VERSION 5.7 ;
  NOWIREEXTENSIONATPIN ON ;
  DIVIDERCHAR "/" ;
  BUSBITCHARS "[]" ;
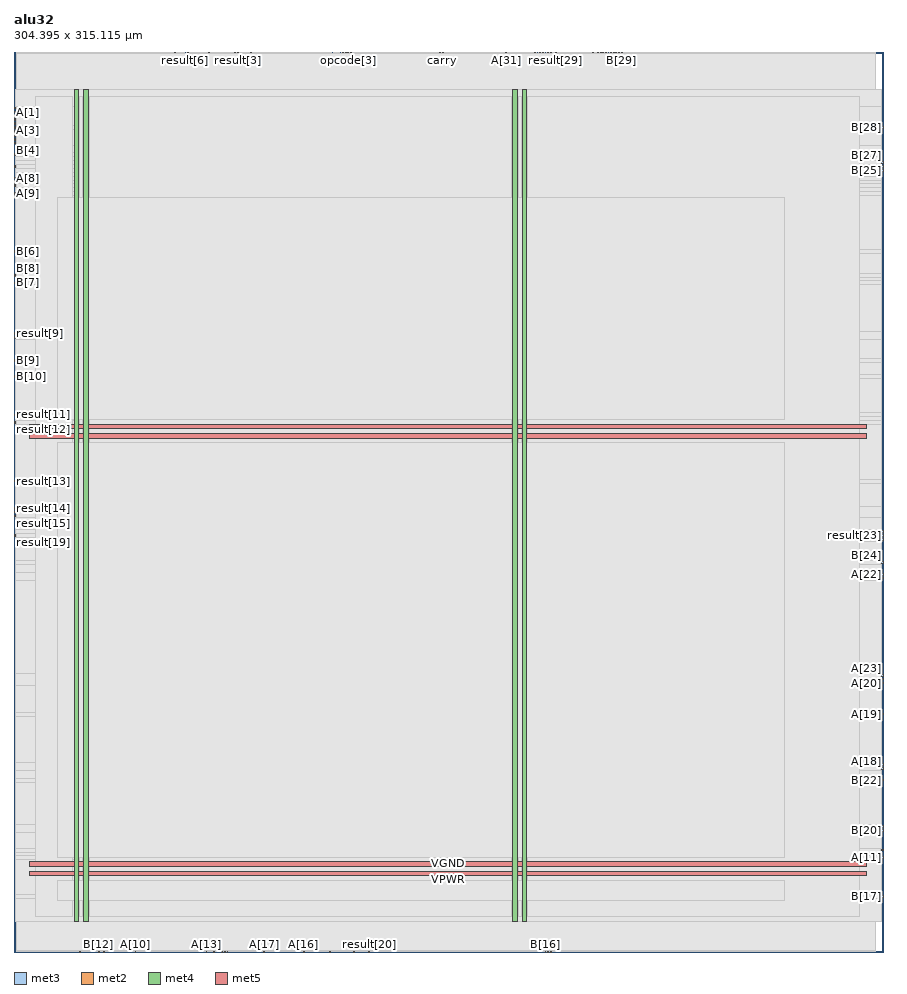
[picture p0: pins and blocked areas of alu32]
MACRO alu32
  CLASS BLOCK ;
  FOREIGN alu32 ;
  ORIGIN 0.000 0.000 ;
  SIZE 304.395 BY 315.115 ;
  PIN A[0]
    DIRECTION INPUT ;
    USE SIGNAL ;
    ANTENNAGATEAREA 0.126000 ;
    PORT
      LAYER met3 ;
        RECT 0.000 292.440 0.600 293.040 ;
    END
  END A[0]
  PIN A[10]
    DIRECTION INPUT ;
    USE SIGNAL ;
    ANTENNAGATEAREA 0.213000 ;
    PORT
      LAYER met2 ;
        RECT 42.410 0.000 42.690 0.280 ;
    END
  END A[10]
  PIN A[11]
    DIRECTION INPUT ;
    USE SIGNAL ;
    ANTENNAGATEAREA 0.213000 ;
    PORT
      LAYER met3 ;
        RECT 303.795 32.680 304.395 33.280 ;
    END
  END A[11]
  PIN A[12]
    DIRECTION INPUT ;
    USE SIGNAL ;
    ANTENNAGATEAREA 0.247500 ;
    PORT
      LAYER met3 ;
        RECT 303.795 35.400 304.395 36.000 ;
    END
  END A[12]
  PIN A[13]
    DIRECTION INPUT ;
    USE SIGNAL ;
    ANTENNAGATEAREA 0.196500 ;
    PORT
      LAYER met2 ;
        RECT 67.250 0.000 67.530 0.280 ;
    END
  END A[13]
  PIN A[14]
    DIRECTION INPUT ;
    USE SIGNAL ;
    ANTENNAGATEAREA 0.213000 ;
    PORT
      LAYER met2 ;
        RECT 70.010 0.000 70.290 0.280 ;
    END
  END A[14]
  PIN A[15]
    DIRECTION INPUT ;
    USE SIGNAL ;
    ANTENNAGATEAREA 0.213000 ;
    PORT
      LAYER met2 ;
        RECT 73.690 0.000 73.970 0.280 ;
    END
  END A[15]
  PIN A[16]
    DIRECTION INPUT ;
    USE SIGNAL ;
    ANTENNAGATEAREA 0.213000 ;
    PORT
      LAYER met2 ;
        RECT 101.290 0.000 101.570 0.280 ;
    END
  END A[16]
  PIN A[17]
    DIRECTION INPUT ;
    USE SIGNAL ;
    ANTENNAGATEAREA 0.196500 ;
    PORT
      LAYER met2 ;
        RECT 87.490 0.000 87.770 0.280 ;
    END
  END A[17]
  PIN A[18]
    DIRECTION INPUT ;
    USE SIGNAL ;
    ANTENNAGATEAREA 0.213000 ;
    PORT
      LAYER met3 ;
        RECT 303.795 63.960 304.395 64.560 ;
    END
  END A[18]
  PIN A[19]
    DIRECTION INPUT ;
    USE SIGNAL ;
    ANTENNAGATEAREA 0.213000 ;
    PORT
      LAYER met3 ;
        RECT 303.795 83.000 304.395 83.600 ;
    END
  END A[19]
  PIN A[1]
    DIRECTION INPUT ;
    USE SIGNAL ;
    ANTENNAGATEAREA 0.495000 ;
    PORT
      LAYER met3 ;
        RECT 0.000 293.800 0.600 294.400 ;
    END
  END A[1]
  PIN A[20]
    DIRECTION INPUT ;
    USE SIGNAL ;
    ANTENNAGATEAREA 0.213000 ;
    PORT
      LAYER met3 ;
        RECT 303.795 93.880 304.395 94.480 ;
    END
  END A[20]
  PIN A[21]
    DIRECTION INPUT ;
    USE SIGNAL ;
    ANTENNAGATEAREA 0.126000 ;
    PORT
      LAYER met3 ;
        RECT 303.795 95.240 304.395 95.840 ;
    END
  END A[21]
  PIN A[22]
    DIRECTION INPUT ;
    USE SIGNAL ;
    ANTENNAGATEAREA 0.126000 ;
    PORT
      LAYER met3 ;
        RECT 303.795 131.960 304.395 132.560 ;
    END
  END A[22]
  PIN A[23]
    DIRECTION INPUT ;
    USE SIGNAL ;
    ANTENNAGATEAREA 0.213000 ;
    PORT
      LAYER met3 ;
        RECT 303.795 96.600 304.395 97.200 ;
    END
  END A[23]
  PIN A[24]
    DIRECTION INPUT ;
    USE SIGNAL ;
    ANTENNAGATEAREA 0.213000 ;
    PORT
      LAYER met2 ;
        RECT 208.010 314.835 208.290 315.115 ;
    END
  END A[24]
  PIN A[25]
    DIRECTION INPUT ;
    USE SIGNAL ;
    ANTENNAGATEAREA 0.213000 ;
    PORT
      LAYER met2 ;
        RECT 207.090 314.835 207.370 315.115 ;
    END
  END A[25]
  PIN A[26]
    DIRECTION INPUT ;
    USE SIGNAL ;
    ANTENNAGATEAREA 0.213000 ;
    PORT
      LAYER met2 ;
        RECT 210.770 314.835 211.050 315.115 ;
    END
  END A[26]
  PIN A[27]
    DIRECTION INPUT ;
    USE SIGNAL ;
    ANTENNAGATEAREA 0.213000 ;
    PORT
      LAYER met2 ;
        RECT 211.690 314.835 211.970 315.115 ;
    END
  END A[27]
  PIN A[28]
    DIRECTION INPUT ;
    USE SIGNAL ;
    ANTENNAGATEAREA 0.213000 ;
    PORT
      LAYER met2 ;
        RECT 209.850 314.835 210.130 315.115 ;
    END
  END A[28]
  PIN A[29]
    DIRECTION INPUT ;
    USE SIGNAL ;
    ANTENNAGATEAREA 0.213000 ;
    PORT
      LAYER met2 ;
        RECT 208.930 314.835 209.210 315.115 ;
    END
  END A[29]
  PIN A[2]
    DIRECTION INPUT ;
    USE SIGNAL ;
    ANTENNAGATEAREA 0.213000 ;
    PORT
      LAYER met3 ;
        RECT 0.000 291.080 0.600 291.680 ;
    END
  END A[2]
  PIN A[30]
    DIRECTION INPUT ;
    USE SIGNAL ;
    ANTENNAGATEAREA 0.196500 ;
    PORT
      LAYER met2 ;
        RECT 206.170 314.835 206.450 315.115 ;
    END
  END A[30]
  PIN A[31]
    DIRECTION INPUT ;
    USE SIGNAL ;
    ANTENNAGATEAREA 0.213000 ;
    PORT
      LAYER met2 ;
        RECT 172.130 314.835 172.410 315.115 ;
    END
  END A[31]
  PIN A[3]
    DIRECTION INPUT ;
    USE SIGNAL ;
    ANTENNAGATEAREA 0.247500 ;
    PORT
      LAYER met3 ;
        RECT 0.000 289.720 0.600 290.320 ;
    END
  END A[3]
  PIN A[4]
    DIRECTION INPUT ;
    USE SIGNAL ;
    ANTENNAGATEAREA 0.213000 ;
    PORT
      LAYER met3 ;
        RECT 0.000 288.360 0.600 288.960 ;
    END
  END A[4]
  PIN A[5]
    DIRECTION INPUT ;
    USE SIGNAL ;
    ANTENNAGATEAREA 0.213000 ;
    PORT
      LAYER met3 ;
        RECT 0.000 287.000 0.600 287.600 ;
    END
  END A[5]
  PIN A[6]
    DIRECTION INPUT ;
    USE SIGNAL ;
    ANTENNAGATEAREA 0.213000 ;
    PORT
      LAYER met3 ;
        RECT 0.000 278.840 0.600 279.440 ;
    END
  END A[6]
  PIN A[7]
    DIRECTION INPUT ;
    USE SIGNAL ;
    ANTENNAGATEAREA 0.247500 ;
    PORT
      LAYER met3 ;
        RECT 0.000 274.760 0.600 275.360 ;
    END
  END A[7]
  PIN A[8]
    DIRECTION INPUT ;
    USE SIGNAL ;
    ANTENNAGATEAREA 0.159000 ;
    PORT
      LAYER met3 ;
        RECT 0.000 270.680 0.600 271.280 ;
    END
  END A[8]
  PIN A[9]
    DIRECTION INPUT ;
    USE SIGNAL ;
    ANTENNAGATEAREA 0.213000 ;
    PORT
      LAYER met3 ;
        RECT 0.000 265.240 0.600 265.840 ;
    END
  END A[9]
  PIN B[0]
    DIRECTION INPUT ;
    USE SIGNAL ;
    ANTENNAGATEAREA 0.213000 ;
    PORT
      LAYER met2 ;
        RECT 205.250 314.835 205.530 315.115 ;
    END
  END B[0]
  PIN B[10]
    DIRECTION INPUT ;
    USE SIGNAL ;
    ANTENNAGATEAREA 0.126000 ;
    PORT
      LAYER met3 ;
        RECT 0.000 201.320 0.600 201.920 ;
    END
  END B[10]
  PIN B[11]
    DIRECTION INPUT ;
    USE SIGNAL ;
    ANTENNAGATEAREA 0.213000 ;
    PORT
      LAYER met2 ;
        RECT 23.090 0.000 23.370 0.280 ;
    END
  END B[11]
  PIN B[12]
    DIRECTION INPUT ;
    USE SIGNAL ;
    ANTENNAGATEAREA 0.213000 ;
    PORT
      LAYER met2 ;
        RECT 29.530 0.000 29.810 0.280 ;
    END
  END B[12]
  PIN B[13]
    DIRECTION INPUT ;
    USE SIGNAL ;
    ANTENNAGATEAREA 0.213000 ;
    PORT
      LAYER met2 ;
        RECT 31.370 0.000 31.650 0.280 ;
    END
  END B[13]
  PIN B[14]
    DIRECTION INPUT ;
    USE SIGNAL ;
    ANTENNAGATEAREA 0.126000 ;
    PORT
      LAYER met2 ;
        RECT 72.770 0.000 73.050 0.280 ;
    END
  END B[14]
  PIN B[15]
    DIRECTION INPUT ;
    USE SIGNAL ;
    ANTENNAGATEAREA 0.126000 ;
    PORT
      LAYER met2 ;
        RECT 74.610 0.000 74.890 0.280 ;
    END
  END B[15]
  PIN B[16]
    DIRECTION INPUT ;
    USE SIGNAL ;
    ANTENNAGATEAREA 0.159000 ;
    PORT
      LAYER met2 ;
        RECT 185.930 0.000 186.210 0.280 ;
    END
  END B[16]
  PIN B[17]
    DIRECTION INPUT ;
    USE SIGNAL ;
    ANTENNAGATEAREA 0.213000 ;
    PORT
      LAYER met3 ;
        RECT 303.795 19.080 304.395 19.680 ;
    END
  END B[17]
  PIN B[18]
    DIRECTION INPUT ;
    USE SIGNAL ;
    ANTENNAGATEAREA 0.213000 ;
    PORT
      LAYER met2 ;
        RECT 186.850 0.000 187.130 0.280 ;
    END
  END B[18]
  PIN B[19]
    DIRECTION INPUT ;
    USE SIGNAL ;
    ANTENNAGATEAREA 0.213000 ;
    PORT
      LAYER met2 ;
        RECT 187.770 0.000 188.050 0.280 ;
    END
  END B[19]
  PIN B[1]
    DIRECTION INPUT ;
    USE SIGNAL ;
    ANTENNAGATEAREA 0.213000 ;
    PORT
      LAYER met3 ;
        RECT 0.000 295.160 0.600 295.760 ;
    END
  END B[1]
  PIN B[20]
    DIRECTION INPUT ;
    USE SIGNAL ;
    ANTENNAGATEAREA 0.213000 ;
    PORT
      LAYER met3 ;
        RECT 303.795 42.200 304.395 42.800 ;
    END
  END B[20]
  PIN B[21]
    DIRECTION INPUT ;
    USE SIGNAL ;
    ANTENNAGATEAREA 0.213000 ;
    PORT
      LAYER met3 ;
        RECT 303.795 43.560 304.395 44.160 ;
    END
  END B[21]
  PIN B[22]
    DIRECTION INPUT ;
    USE SIGNAL ;
    ANTENNAGATEAREA 0.213000 ;
    PORT
      LAYER met3 ;
        RECT 303.795 59.880 304.395 60.480 ;
    END
  END B[22]
  PIN B[23]
    DIRECTION INPUT ;
    USE SIGNAL ;
    ANTENNAGATEAREA 0.213000 ;
    PORT
      LAYER met3 ;
        RECT 303.795 65.320 304.395 65.920 ;
    END
  END B[23]
  PIN B[24]
    DIRECTION INPUT ;
    USE SIGNAL ;
    ANTENNAGATEAREA 0.213000 ;
    PORT
      LAYER met3 ;
        RECT 303.795 136.040 304.395 136.640 ;
    END
  END B[24]
  PIN B[25]
    DIRECTION INPUT ;
    USE SIGNAL ;
    ANTENNAGATEAREA 0.213000 ;
    PORT
      LAYER met3 ;
        RECT 303.795 273.400 304.395 274.000 ;
    END
  END B[25]
  PIN B[26]
    DIRECTION INPUT ;
    USE SIGNAL ;
    ANTENNAGATEAREA 0.213000 ;
    PORT
      LAYER met3 ;
        RECT 303.795 274.760 304.395 275.360 ;
    END
  END B[26]
  PIN B[27]
    DIRECTION INPUT ;
    USE SIGNAL ;
    ANTENNAGATEAREA 0.213000 ;
    PORT
      LAYER met3 ;
        RECT 303.795 276.120 304.395 276.720 ;
    END
  END B[27]
  PIN B[28]
    DIRECTION INPUT ;
    USE SIGNAL ;
    ANTENNAGATEAREA 0.196500 ;
    PORT
      LAYER met3 ;
        RECT 303.795 288.360 304.395 288.960 ;
    END
  END B[28]
  PIN B[29]
    DIRECTION INPUT ;
    USE SIGNAL ;
    ANTENNAGATEAREA 0.213000 ;
    PORT
      LAYER met2 ;
        RECT 212.610 314.835 212.890 315.115 ;
    END
  END B[29]
  PIN B[2]
    DIRECTION INPUT ;
    USE SIGNAL ;
    ANTENNAGATEAREA 0.213000 ;
    PORT
      LAYER met3 ;
        RECT 0.000 285.640 0.600 286.240 ;
    END
  END B[2]
  PIN B[30]
    DIRECTION INPUT ;
    USE SIGNAL ;
    ANTENNAGATEAREA 0.213000 ;
    PORT
      LAYER met2 ;
        RECT 204.330 314.835 204.610 315.115 ;
    END
  END B[30]
  PIN B[31]
    DIRECTION INPUT ;
    USE SIGNAL ;
    ANTENNAGATEAREA 0.213000 ;
    PORT
      LAYER met2 ;
        RECT 202.490 314.835 202.770 315.115 ;
    END
  END B[31]
  PIN B[3]
    DIRECTION INPUT ;
    USE SIGNAL ;
    ANTENNAGATEAREA 0.213000 ;
    PORT
      LAYER met3 ;
        RECT 0.000 284.280 0.600 284.880 ;
    END
  END B[3]
  PIN B[4]
    DIRECTION INPUT ;
    USE SIGNAL ;
    ANTENNAGATEAREA 0.213000 ;
    PORT
      LAYER met3 ;
        RECT 0.000 282.920 0.600 283.520 ;
    END
  END B[4]
  PIN B[5]
    DIRECTION INPUT ;
    USE SIGNAL ;
    ANTENNAGATEAREA 0.213000 ;
    PORT
      LAYER met3 ;
        RECT 0.000 267.960 0.600 268.560 ;
    END
  END B[5]
  PIN B[6]
    DIRECTION INPUT ;
    USE SIGNAL ;
    ANTENNAGATEAREA 0.742500 ;
    PORT
      LAYER met3 ;
        RECT 0.000 244.840 0.600 245.440 ;
    END
  END B[6]
  PIN B[7]
    DIRECTION INPUT ;
    USE SIGNAL ;
    ANTENNAGATEAREA 0.495000 ;
    PORT
      LAYER met3 ;
        RECT 0.000 233.960 0.600 234.560 ;
    END
  END B[7]
  PIN B[8]
    DIRECTION INPUT ;
    USE SIGNAL ;
    ANTENNAGATEAREA 0.213000 ;
    PORT
      LAYER met3 ;
        RECT 0.000 236.680 0.600 237.280 ;
    END
  END B[8]
  PIN B[9]
    DIRECTION INPUT ;
    USE SIGNAL ;
    ANTENNAGATEAREA 0.213000 ;
    PORT
      LAYER met3 ;
        RECT 0.000 206.760 0.600 207.360 ;
    END
  END B[9]
  PIN VGND
    DIRECTION INOUT ;
    USE GROUND ;
    PORT
      LAYER met4 ;
        RECT 24.340 10.640 25.940 302.160 ;
    END
    PORT
      LAYER met4 ;
        RECT 177.940 10.640 179.540 302.160 ;
    END
    PORT
      LAYER met5 ;
        RECT 5.520 30.030 298.540 31.630 ;
    END
    PORT
      LAYER met5 ;
        RECT 5.520 183.210 298.540 184.810 ;
    END
  END VGND
  PIN VPWR
    DIRECTION INOUT ;
    USE POWER ;
    PORT
      LAYER met4 ;
        RECT 21.040 10.640 22.640 302.160 ;
    END
    PORT
      LAYER met4 ;
        RECT 174.640 10.640 176.240 302.160 ;
    END
    PORT
      LAYER met5 ;
        RECT 5.520 26.730 298.540 28.330 ;
    END
    PORT
      LAYER met5 ;
        RECT 5.520 179.910 298.540 181.510 ;
    END
  END VPWR
  PIN carry
    DIRECTION OUTPUT ;
    USE SIGNAL ;
    ANTENNADIFFAREA 0.702900 ;
    PORT
      LAYER met2 ;
        RECT 150.050 314.835 150.330 315.115 ;
    END
  END carry
  PIN opcode[0]
    DIRECTION INPUT ;
    USE SIGNAL ;
    ANTENNAGATEAREA 0.213000 ;
    PORT
      LAYER met2 ;
        RECT 115.090 314.835 115.370 315.115 ;
    END
  END opcode[0]
  PIN opcode[1]
    DIRECTION INPUT ;
    USE SIGNAL ;
    ANTENNAGATEAREA 0.213000 ;
    PORT
      LAYER met2 ;
        RECT 117.850 314.835 118.130 315.115 ;
    END
  END opcode[1]
  PIN opcode[2]
    DIRECTION INPUT ;
    USE SIGNAL ;
    ANTENNAGATEAREA 0.213000 ;
    PORT
      LAYER met2 ;
        RECT 116.010 314.835 116.290 315.115 ;
    END
  END opcode[2]
  PIN opcode[3]
    DIRECTION INPUT ;
    USE SIGNAL ;
    ANTENNAGATEAREA 0.213000 ;
    PORT
      LAYER met2 ;
        RECT 116.930 314.835 117.210 315.115 ;
    END
  END opcode[3]
  PIN overflow
    DIRECTION OUTPUT ;
    USE SIGNAL ;
    ANTENNADIFFAREA 1.782000 ;
    PORT
      LAYER met2 ;
        RECT 149.130 314.835 149.410 315.115 ;
    END
  END overflow
  PIN result[0]
    DIRECTION OUTPUT ;
    USE SIGNAL ;
    ANTENNADIFFAREA 0.702900 ;
    PORT
      LAYER met2 ;
        RECT 114.170 314.835 114.450 315.115 ;
    END
  END result[0]
  PIN result[10]
    DIRECTION OUTPUT ;
    USE SIGNAL ;
    ANTENNADIFFAREA 0.702900 ;
    PORT
      LAYER met3 ;
        RECT 0.000 214.920 0.600 215.520 ;
    END
  END result[10]
  PIN result[11]
    DIRECTION OUTPUT ;
    USE SIGNAL ;
    ANTENNADIFFAREA 0.702900 ;
    PORT
      LAYER met3 ;
        RECT 0.000 187.720 0.600 188.320 ;
    END
  END result[11]
  PIN result[12]
    DIRECTION OUTPUT ;
    USE SIGNAL ;
    ANTENNADIFFAREA 0.702900 ;
    PORT
      LAYER met3 ;
        RECT 0.000 185.000 0.600 185.600 ;
    END
  END result[12]
  PIN result[13]
    DIRECTION OUTPUT ;
    USE SIGNAL ;
    ANTENNADIFFAREA 0.702900 ;
    PORT
      LAYER met3 ;
        RECT 0.000 164.600 0.600 165.200 ;
    END
  END result[13]
  PIN result[14]
    DIRECTION OUTPUT ;
    USE SIGNAL ;
    ANTENNADIFFAREA 0.702900 ;
    PORT
      LAYER met3 ;
        RECT 0.000 155.080 0.600 155.680 ;
    END
  END result[14]
  PIN result[15]
    DIRECTION OUTPUT ;
    USE SIGNAL ;
    ANTENNADIFFAREA 0.702900 ;
    PORT
      LAYER met3 ;
        RECT 0.000 152.360 0.600 152.960 ;
    END
  END result[15]
  PIN result[16]
    DIRECTION OUTPUT ;
    USE SIGNAL ;
    ANTENNADIFFAREA 0.702900 ;
    PORT
      LAYER met3 ;
        RECT 0.000 153.720 0.600 154.320 ;
    END
  END result[16]
  PIN result[17]
    DIRECTION OUTPUT ;
    USE SIGNAL ;
    ANTENNADIFFAREA 0.702900 ;
    PORT
      LAYER met2 ;
        RECT 110.490 0.000 110.770 0.280 ;
    END
  END result[17]
  PIN result[18]
    DIRECTION OUTPUT ;
    USE SIGNAL ;
    ANTENNADIFFAREA 0.702900 ;
    PORT
      LAYER met2 ;
        RECT 118.770 0.000 119.050 0.280 ;
    END
  END result[18]
  PIN result[19]
    DIRECTION OUTPUT ;
    USE SIGNAL ;
    ANTENNADIFFAREA 0.702900 ;
    PORT
      LAYER met3 ;
        RECT 0.000 145.560 0.600 146.160 ;
    END
  END result[19]
  PIN result[1]
    DIRECTION OUTPUT ;
    USE SIGNAL ;
    ANTENNADIFFAREA 0.702900 ;
    PORT
      LAYER met2 ;
        RECT 111.410 314.835 111.690 315.115 ;
    END
  END result[1]
  PIN result[20]
    DIRECTION OUTPUT ;
    USE SIGNAL ;
    ANTENNADIFFAREA 0.702900 ;
    PORT
      LAYER met2 ;
        RECT 124.290 0.000 124.570 0.280 ;
    END
  END result[20]
  PIN result[21]
    DIRECTION OUTPUT ;
    USE SIGNAL ;
    ANTENNADIFFAREA 0.702900 ;
    PORT
      LAYER met3 ;
        RECT 303.795 144.200 304.395 144.800 ;
    END
  END result[21]
  PIN result[22]
    DIRECTION OUTPUT ;
    USE SIGNAL ;
    ANTENNADIFFAREA 0.702900 ;
    PORT
      LAYER met3 ;
        RECT 303.795 146.920 304.395 147.520 ;
    END
  END result[22]
  PIN result[23]
    DIRECTION OUTPUT ;
    USE SIGNAL ;
    ANTENNADIFFAREA 0.702900 ;
    PORT
      LAYER met3 ;
        RECT 303.795 145.560 304.395 146.160 ;
    END
  END result[23]
  PIN result[24]
    DIRECTION OUTPUT ;
    USE SIGNAL ;
    ANTENNADIFFAREA 0.702900 ;
    PORT
      LAYER met3 ;
        RECT 303.795 130.600 304.395 131.200 ;
    END
  END result[24]
  PIN result[25]
    DIRECTION OUTPUT ;
    USE SIGNAL ;
    ANTENNADIFFAREA 0.702900 ;
    PORT
      LAYER met2 ;
        RECT 182.250 314.835 182.530 315.115 ;
    END
  END result[25]
  PIN result[26]
    DIRECTION OUTPUT ;
    USE SIGNAL ;
    ANTENNADIFFAREA 0.702900 ;
    PORT
      LAYER met2 ;
        RECT 184.090 314.835 184.370 315.115 ;
    END
  END result[26]
  PIN result[27]
    DIRECTION OUTPUT ;
    USE SIGNAL ;
    ANTENNADIFFAREA 1.336500 ;
    PORT
      LAYER met2 ;
        RECT 185.930 314.835 186.210 315.115 ;
    END
  END result[27]
  PIN result[28]
    DIRECTION OUTPUT ;
    USE SIGNAL ;
    ANTENNADIFFAREA 0.383400 ;
    PORT
      LAYER met2 ;
        RECT 185.010 314.835 185.290 315.115 ;
    END
  END result[28]
  PIN result[29]
    DIRECTION OUTPUT ;
    USE SIGNAL ;
    ANTENNAGATEAREA 0.126000 ;
    ANTENNADIFFAREA 0.429000 ;
    PORT
      LAYER met2 ;
        RECT 189.610 314.835 189.890 315.115 ;
    END
  END result[29]
  PIN result[2]
    DIRECTION OUTPUT ;
    USE SIGNAL ;
    ANTENNADIFFAREA 0.702900 ;
    PORT
      LAYER met2 ;
        RECT 82.890 314.835 83.170 315.115 ;
    END
  END result[2]
  PIN result[30]
    DIRECTION OUTPUT ;
    USE SIGNAL ;
    ANTENNADIFFAREA 0.383400 ;
    PORT
      LAYER met2 ;
        RECT 186.850 314.835 187.130 315.115 ;
    END
  END result[30]
  PIN result[31]
    DIRECTION OUTPUT ;
    USE SIGNAL ;
    ANTENNADIFFAREA 1.782000 ;
    PORT
      LAYER met2 ;
        RECT 183.170 314.835 183.450 315.115 ;
    END
  END result[31]
  PIN result[3]
    DIRECTION OUTPUT ;
    USE SIGNAL ;
    ANTENNADIFFAREA 0.702900 ;
    PORT
      LAYER met2 ;
        RECT 78.290 314.835 78.570 315.115 ;
    END
  END result[3]
  PIN result[4]
    DIRECTION OUTPUT ;
    USE SIGNAL ;
    ANTENNADIFFAREA 0.702900 ;
    PORT
      LAYER met2 ;
        RECT 77.370 314.835 77.650 315.115 ;
    END
  END result[4]
  PIN result[5]
    DIRECTION OUTPUT ;
    USE SIGNAL ;
    ANTENNADIFFAREA 0.702900 ;
    PORT
      LAYER met2 ;
        RECT 68.170 314.835 68.450 315.115 ;
    END
  END result[5]
  PIN result[6]
    DIRECTION OUTPUT ;
    USE SIGNAL ;
    ANTENNADIFFAREA 0.702900 ;
    PORT
      LAYER met2 ;
        RECT 59.890 314.835 60.170 315.115 ;
    END
  END result[6]
  PIN result[7]
    DIRECTION OUTPUT ;
    USE SIGNAL ;
    ANTENNADIFFAREA 0.702900 ;
    PORT
      LAYER met2 ;
        RECT 60.810 314.835 61.090 315.115 ;
    END
  END result[7]
  PIN result[8]
    DIRECTION OUTPUT ;
    USE SIGNAL ;
    ANTENNADIFFAREA 0.702900 ;
    PORT
      LAYER met2 ;
        RECT 56.210 314.835 56.490 315.115 ;
    END
  END result[8]
  PIN result[9]
    DIRECTION OUTPUT ;
    USE SIGNAL ;
    ANTENNADIFFAREA 0.702900 ;
    PORT
      LAYER met3 ;
        RECT 0.000 216.280 0.600 216.880 ;
    END
  END result[9]
  PIN zero
    DIRECTION OUTPUT ;
    USE SIGNAL ;
    ANTENNADIFFAREA 1.336500 ;
    PORT
      LAYER met2 ;
        RECT 187.770 314.835 188.050 315.115 ;
    END
  END zero
  OBS
      LAYER nwell ;
        RECT 5.330 10.795 298.730 302.110 ;
      LAYER li1 ;
        RECT 5.520 10.795 298.540 302.005 ;
      LAYER met1 ;
        RECT 0.990 10.240 301.690 302.900 ;
      LAYER met2 ;
        RECT 1.010 314.555 55.930 314.835 ;
        RECT 56.770 314.555 59.610 314.835 ;
        RECT 60.450 314.555 60.530 314.835 ;
        RECT 61.370 314.555 67.890 314.835 ;
        RECT 68.730 314.555 77.090 314.835 ;
        RECT 77.930 314.555 78.010 314.835 ;
        RECT 78.850 314.555 82.610 314.835 ;
        RECT 83.450 314.555 111.130 314.835 ;
        RECT 111.970 314.555 113.890 314.835 ;
        RECT 114.730 314.555 114.810 314.835 ;
        RECT 115.650 314.555 115.730 314.835 ;
        RECT 116.570 314.555 116.650 314.835 ;
        RECT 117.490 314.555 117.570 314.835 ;
        RECT 118.410 314.555 148.850 314.835 ;
        RECT 149.690 314.555 149.770 314.835 ;
        RECT 150.610 314.555 171.850 314.835 ;
        RECT 172.690 314.555 181.970 314.835 ;
        RECT 182.810 314.555 182.890 314.835 ;
        RECT 183.730 314.555 183.810 314.835 ;
        RECT 184.650 314.555 184.730 314.835 ;
        RECT 185.570 314.555 185.650 314.835 ;
        RECT 186.490 314.555 186.570 314.835 ;
        RECT 187.410 314.555 187.490 314.835 ;
        RECT 188.330 314.555 189.330 314.835 ;
        RECT 190.170 314.555 202.210 314.835 ;
        RECT 203.050 314.555 204.050 314.835 ;
        RECT 204.890 314.555 204.970 314.835 ;
        RECT 205.810 314.555 205.890 314.835 ;
        RECT 206.730 314.555 206.810 314.835 ;
        RECT 207.650 314.555 207.730 314.835 ;
        RECT 208.570 314.555 208.650 314.835 ;
        RECT 209.490 314.555 209.570 314.835 ;
        RECT 210.410 314.555 210.490 314.835 ;
        RECT 211.330 314.555 211.410 314.835 ;
        RECT 212.250 314.555 212.330 314.835 ;
        RECT 213.170 314.555 301.670 314.835 ;
        RECT 1.010 0.560 301.670 314.555 ;
        RECT 1.010 0.280 22.810 0.560 ;
        RECT 23.650 0.280 29.250 0.560 ;
        RECT 30.090 0.280 31.090 0.560 ;
        RECT 31.930 0.280 42.130 0.560 ;
        RECT 42.970 0.280 66.970 0.560 ;
        RECT 67.810 0.280 69.730 0.560 ;
        RECT 70.570 0.280 72.490 0.560 ;
        RECT 73.330 0.280 73.410 0.560 ;
        RECT 74.250 0.280 74.330 0.560 ;
        RECT 75.170 0.280 87.210 0.560 ;
        RECT 88.050 0.280 101.010 0.560 ;
        RECT 101.850 0.280 110.210 0.560 ;
        RECT 111.050 0.280 118.490 0.560 ;
        RECT 119.330 0.280 124.010 0.560 ;
        RECT 124.850 0.280 185.650 0.560 ;
        RECT 186.490 0.280 186.570 0.560 ;
        RECT 187.410 0.280 187.490 0.560 ;
        RECT 188.330 0.280 301.670 0.560 ;
      LAYER met3 ;
        RECT 0.600 296.160 303.795 302.085 ;
        RECT 1.000 289.360 303.795 296.160 ;
        RECT 1.000 287.960 303.395 289.360 ;
        RECT 1.000 282.520 303.795 287.960 ;
        RECT 0.600 279.840 303.795 282.520 ;
        RECT 1.000 278.440 303.795 279.840 ;
        RECT 0.600 277.120 303.795 278.440 ;
        RECT 0.600 275.760 303.395 277.120 ;
        RECT 1.000 274.360 303.395 275.760 ;
        RECT 0.600 273.000 303.395 274.360 ;
        RECT 0.600 271.680 303.795 273.000 ;
        RECT 1.000 270.280 303.795 271.680 ;
        RECT 0.600 268.960 303.795 270.280 ;
        RECT 1.000 267.560 303.795 268.960 ;
        RECT 0.600 266.240 303.795 267.560 ;
        RECT 1.000 264.840 303.795 266.240 ;
        RECT 0.600 245.840 303.795 264.840 ;
        RECT 1.000 244.440 303.795 245.840 ;
        RECT 0.600 237.680 303.795 244.440 ;
        RECT 1.000 236.280 303.795 237.680 ;
        RECT 0.600 234.960 303.795 236.280 ;
        RECT 1.000 233.560 303.795 234.960 ;
        RECT 0.600 217.280 303.795 233.560 ;
        RECT 1.000 214.520 303.795 217.280 ;
        RECT 0.600 207.760 303.795 214.520 ;
        RECT 1.000 206.360 303.795 207.760 ;
        RECT 0.600 202.320 303.795 206.360 ;
        RECT 1.000 200.920 303.795 202.320 ;
        RECT 0.600 188.720 303.795 200.920 ;
        RECT 1.000 187.320 303.795 188.720 ;
        RECT 0.600 186.000 303.795 187.320 ;
        RECT 1.000 184.600 303.795 186.000 ;
        RECT 0.600 165.600 303.795 184.600 ;
        RECT 1.000 164.200 303.795 165.600 ;
        RECT 0.600 156.080 303.795 164.200 ;
        RECT 1.000 151.960 303.795 156.080 ;
        RECT 0.600 147.920 303.795 151.960 ;
        RECT 0.600 146.560 303.395 147.920 ;
        RECT 1.000 145.160 303.395 146.560 ;
        RECT 0.600 143.800 303.395 145.160 ;
        RECT 0.600 137.040 303.795 143.800 ;
        RECT 0.600 135.640 303.395 137.040 ;
        RECT 0.600 132.960 303.795 135.640 ;
        RECT 0.600 130.200 303.395 132.960 ;
        RECT 0.600 97.600 303.795 130.200 ;
        RECT 0.600 93.480 303.395 97.600 ;
        RECT 0.600 84.000 303.795 93.480 ;
        RECT 0.600 82.600 303.395 84.000 ;
        RECT 0.600 66.320 303.795 82.600 ;
        RECT 0.600 63.560 303.395 66.320 ;
        RECT 0.600 60.880 303.795 63.560 ;
        RECT 0.600 59.480 303.395 60.880 ;
        RECT 0.600 44.560 303.795 59.480 ;
        RECT 0.600 41.800 303.395 44.560 ;
        RECT 0.600 36.400 303.795 41.800 ;
        RECT 0.600 35.000 303.395 36.400 ;
        RECT 0.600 33.680 303.795 35.000 ;
        RECT 0.600 32.280 303.395 33.680 ;
        RECT 0.600 20.080 303.795 32.280 ;
        RECT 0.600 18.680 303.395 20.080 ;
        RECT 0.600 10.715 303.795 18.680 ;
      LAYER met4 ;
        RECT 7.655 12.415 20.640 299.705 ;
        RECT 23.040 12.415 23.940 299.705 ;
        RECT 26.340 12.415 174.240 299.705 ;
        RECT 176.640 12.415 177.540 299.705 ;
        RECT 179.940 12.415 295.945 299.705 ;
      LAYER met5 ;
        RECT 15.300 186.410 269.900 264.300 ;
        RECT 15.300 33.230 269.900 178.310 ;
        RECT 15.300 17.900 269.900 25.130 ;
  END
END alu32
END LIBRARY

